VERSION 5.8 ;
BUSBITCHARS "[]" ;
DIVIDERCHAR "/" ;
UNITS
    DATABASE MICRONS 1000 ;
END UNITS

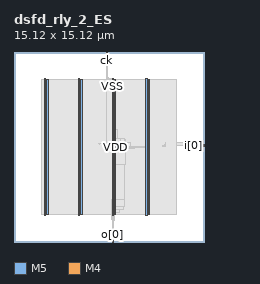
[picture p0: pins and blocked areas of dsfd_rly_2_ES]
MACRO dsfd_rly_2_ES
  FOREIGN dsfd_rly_2_ES 0 0 ;
  CLASS BLOCK ;
  SIZE 15.12 BY 15.12 ;
  PIN ck
    DIRECTION INPUT ;
    USE SIGNAL ;
    PORT
      LAYER M5 ;
        RECT  7.344 15.036 7.368 15.12 ;
    END
  END ck
  PIN i[0]
    DIRECTION INPUT ;
    USE SIGNAL ;
    PORT
      LAYER M4 ;
        RECT  15.036 7.632 15.12 7.656 ;
    END
  END i[0]
  PIN i[1]
    DIRECTION INPUT ;
    USE SIGNAL ;
    PORT
      LAYER M4 ;
        RECT  15.036 7.728 15.12 7.752 ;
    END
  END i[1]
  PIN o[0]
    DIRECTION OUTPUT ;
    USE SIGNAL ;
    PORT
      LAYER M5 ;
        RECT  7.824 0 7.848 0.084 ;
    END
  END o[0]
  PIN o[1]
    DIRECTION OUTPUT ;
    USE SIGNAL ;
    PORT
      LAYER M5 ;
        RECT  7.92 0 7.944 0.084 ;
    END
  END o[1]
  PIN rs
    DIRECTION INPUT ;
    USE SIGNAL ;
    PORT
      LAYER M5 ;
        RECT  7.44 15.036 7.464 15.12 ;
    END
  END rs
  PIN VDD
    DIRECTION INOUT ;
    USE POWER ;
    PORT
      LAYER M5 ;
        RECT  10.692 2.151 10.812 12.969 ;
        RECT  7.992 2.151 8.112 12.969 ;
        RECT  5.292 2.151 5.412 12.969 ;
        RECT  2.592 2.151 2.712 12.969 ;
    END
  END VDD
  PIN VSS
    DIRECTION INOUT ;
    USE GROUND ;
    PORT
      LAYER M5 ;
        RECT  10.5 2.137 10.62 12.983 ;
        RECT  7.8 2.137 7.92 12.983 ;
        RECT  5.1 2.137 5.22 12.983 ;
        RECT  2.4 2.137 2.52 12.983 ;
    END
  END VSS
  OBS
    LAYER RVTN ;
     RECT  2.16 2.16 12.96 2.295 ;
     RECT  2.16 2.565 12.96 2.835 ;
     RECT  2.16 3.105 12.96 3.375 ;
     RECT  2.16 3.645 12.96 3.915 ;
     RECT  2.16 4.185 12.96 4.455 ;
     RECT  2.16 4.725 12.96 4.995 ;
     RECT  2.16 5.265 12.96 5.535 ;
     RECT  2.16 5.805 12.96 6.075 ;
     RECT  2.16 6.345 12.96 6.615 ;
     RECT  2.16 6.885 12.96 7.155 ;
     RECT  2.16 7.425 12.96 7.695 ;
     RECT  2.16 7.965 12.96 8.235 ;
     RECT  2.16 8.505 12.96 8.775 ;
     RECT  2.16 9.045 12.96 9.315 ;
     RECT  2.16 9.585 12.96 9.855 ;
     RECT  2.16 10.125 12.96 10.395 ;
     RECT  2.16 10.665 12.96 10.935 ;
     RECT  2.16 11.205 12.96 11.475 ;
     RECT  2.16 11.745 12.96 12.015 ;
     RECT  2.16 12.285 12.96 12.555 ;
     RECT  2.16 12.825 12.96 12.96 ;
    LAYER RVTP ;
     RECT  2.16 2.295 12.96 2.565 ;
     RECT  2.16 2.835 12.96 3.105 ;
     RECT  2.16 3.375 12.96 3.645 ;
     RECT  2.16 3.915 12.96 4.185 ;
     RECT  2.16 4.455 12.96 4.725 ;
     RECT  2.16 4.995 12.96 5.265 ;
     RECT  2.16 5.535 12.96 5.805 ;
     RECT  2.16 6.075 12.96 6.345 ;
     RECT  2.16 6.615 12.96 6.885 ;
     RECT  2.16 7.155 12.96 7.425 ;
     RECT  2.16 7.695 12.96 7.965 ;
     RECT  2.16 8.235 12.96 8.505 ;
     RECT  2.16 8.775 12.96 9.045 ;
     RECT  2.16 9.315 12.96 9.585 ;
     RECT  2.16 9.855 12.96 10.125 ;
     RECT  2.16 10.395 12.96 10.665 ;
     RECT  2.16 10.935 12.96 11.205 ;
     RECT  2.16 11.475 12.96 11.745 ;
     RECT  2.16 12.015 12.96 12.285 ;
     RECT  2.16 12.555 12.96 12.825 ;
    LAYER M1 ;
     RECT  2.16 2.151 12.96 12.969 ;
    LAYER M2 ;
     RECT  2.16 2.151 12.96 12.969 ;
     RECT  12.96 7.668 13.667 7.956 ;
    LAYER M3 ;
     RECT  7.956 1.723 7.974 1.771 ;
     RECT  7.776 1.771 7.974 2.227 ;
     RECT  7.74 2.227 7.974 2.335 ;
     RECT  2.415 2.143 2.505 2.413 ;
     RECT  5.115 2.143 5.205 2.413 ;
     RECT  10.515 2.143 10.605 2.413 ;
     RECT  7.74 2.335 8.37 2.605 ;
     RECT  7.74 2.605 8.694 2.803 ;
     RECT  7.74 2.803 8.766 3.371 ;
     RECT  7.815 3.371 8.766 6.151 ;
     RECT  7.815 6.151 8.838 7.465 ;
     RECT  7.632 7.465 9.558 7.501 ;
     RECT  10.515 2.413 10.797 7.501 ;
     RECT  7.632 7.501 10.797 7.619 ;
     RECT  11.844 7.591 11.862 7.627 ;
     RECT  11.844 7.627 12.042 7.691 ;
     RECT  11.952 7.691 12.042 7.763 ;
     RECT  6.768 7.735 6.786 7.853 ;
     RECT  7.704 7.619 9.306 7.889 ;
     RECT  12.024 7.763 12.042 7.889 ;
     RECT  7.704 7.889 8.946 7.925 ;
     RECT  7.704 7.925 8.91 7.949 ;
     RECT  13.644 7.627 13.662 7.961 ;
     RECT  7.815 7.949 8.91 8.159 ;
     RECT  7.815 8.159 8.802 8.237 ;
     RECT  7.815 8.237 8.262 8.969 ;
     RECT  7.815 8.969 8.097 9.085 ;
     RECT  7.596 9.085 8.097 12.325 ;
     RECT  2.415 2.413 2.697 12.707 ;
     RECT  5.115 2.413 5.397 12.707 ;
     RECT  7.524 12.325 8.097 12.707 ;
     RECT  10.515 7.619 10.797 12.707 ;
     RECT  2.415 12.707 2.505 12.977 ;
     RECT  5.115 12.707 5.205 12.977 ;
     RECT  7.524 12.707 7.905 12.977 ;
     RECT  10.515 12.707 10.605 12.977 ;
     RECT  7.524 12.977 7.542 13.085 ;
    LAYER M4 ;
     RECT  2.408 2.148 2.512 12.972 ;
     RECT  2.512 2.418 2.704 12.702 ;
     RECT  5.108 2.148 5.212 12.972 ;
     RECT  5.212 2.418 5.404 12.702 ;
     RECT  6.757 7.824 7.333 7.848 ;
     RECT  7.429 13.056 7.553 13.08 ;
     RECT  7.333 7.824 7.669 7.944 ;
     RECT  7.765 1.776 7.808 1.8 ;
     RECT  7.669 7.824 7.808 8.232 ;
     RECT  7.808 1.776 7.813 12.972 ;
     RECT  7.813 1.728 7.912 12.972 ;
     RECT  7.912 1.728 7.985 12.702 ;
     RECT  7.985 2.418 8.104 12.702 ;
     RECT  8.104 7.728 8.453 8.232 ;
     RECT  8.453 7.92 8.813 8.232 ;
     RECT  8.813 7.92 8.921 7.944 ;
     RECT  10.508 2.148 10.612 12.972 ;
     RECT  10.612 2.418 10.804 12.702 ;
     RECT  13.633 7.632 15.084 7.752 ;
    LAYER M5 ;
     RECT  7.824 0.016 7.944 2.137 ;
     RECT  2.4 2.137 2.52 2.151 ;
     RECT  5.1 2.137 5.22 2.151 ;
     RECT  7.8 2.137 7.944 2.151 ;
     RECT  10.5 2.137 10.62 2.151 ;
     RECT  7.8 2.151 8.112 7.813 ;
     RECT  7.68 7.813 8.112 7.909 ;
     RECT  2.4 2.151 2.712 12.969 ;
     RECT  5.1 2.151 5.412 12.969 ;
     RECT  7.344 7.909 8.112 12.969 ;
     RECT  10.5 2.151 10.812 12.969 ;
     RECT  2.4 12.969 2.52 12.983 ;
     RECT  5.1 12.969 5.22 12.983 ;
     RECT  7.344 12.969 7.92 12.983 ;
     RECT  10.5 12.969 10.62 12.983 ;
     RECT  7.344 12.983 7.464 15.056 ;
  END
END dsfd_rly_2_ES
END LIBRARY
